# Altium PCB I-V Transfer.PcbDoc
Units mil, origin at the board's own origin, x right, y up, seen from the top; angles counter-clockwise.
Board outline 6000 x 4000 mil, 2 copper layers (Top Layer, Bottom Layer); 23 components, 15 nets, 71 pads, 1 vias.

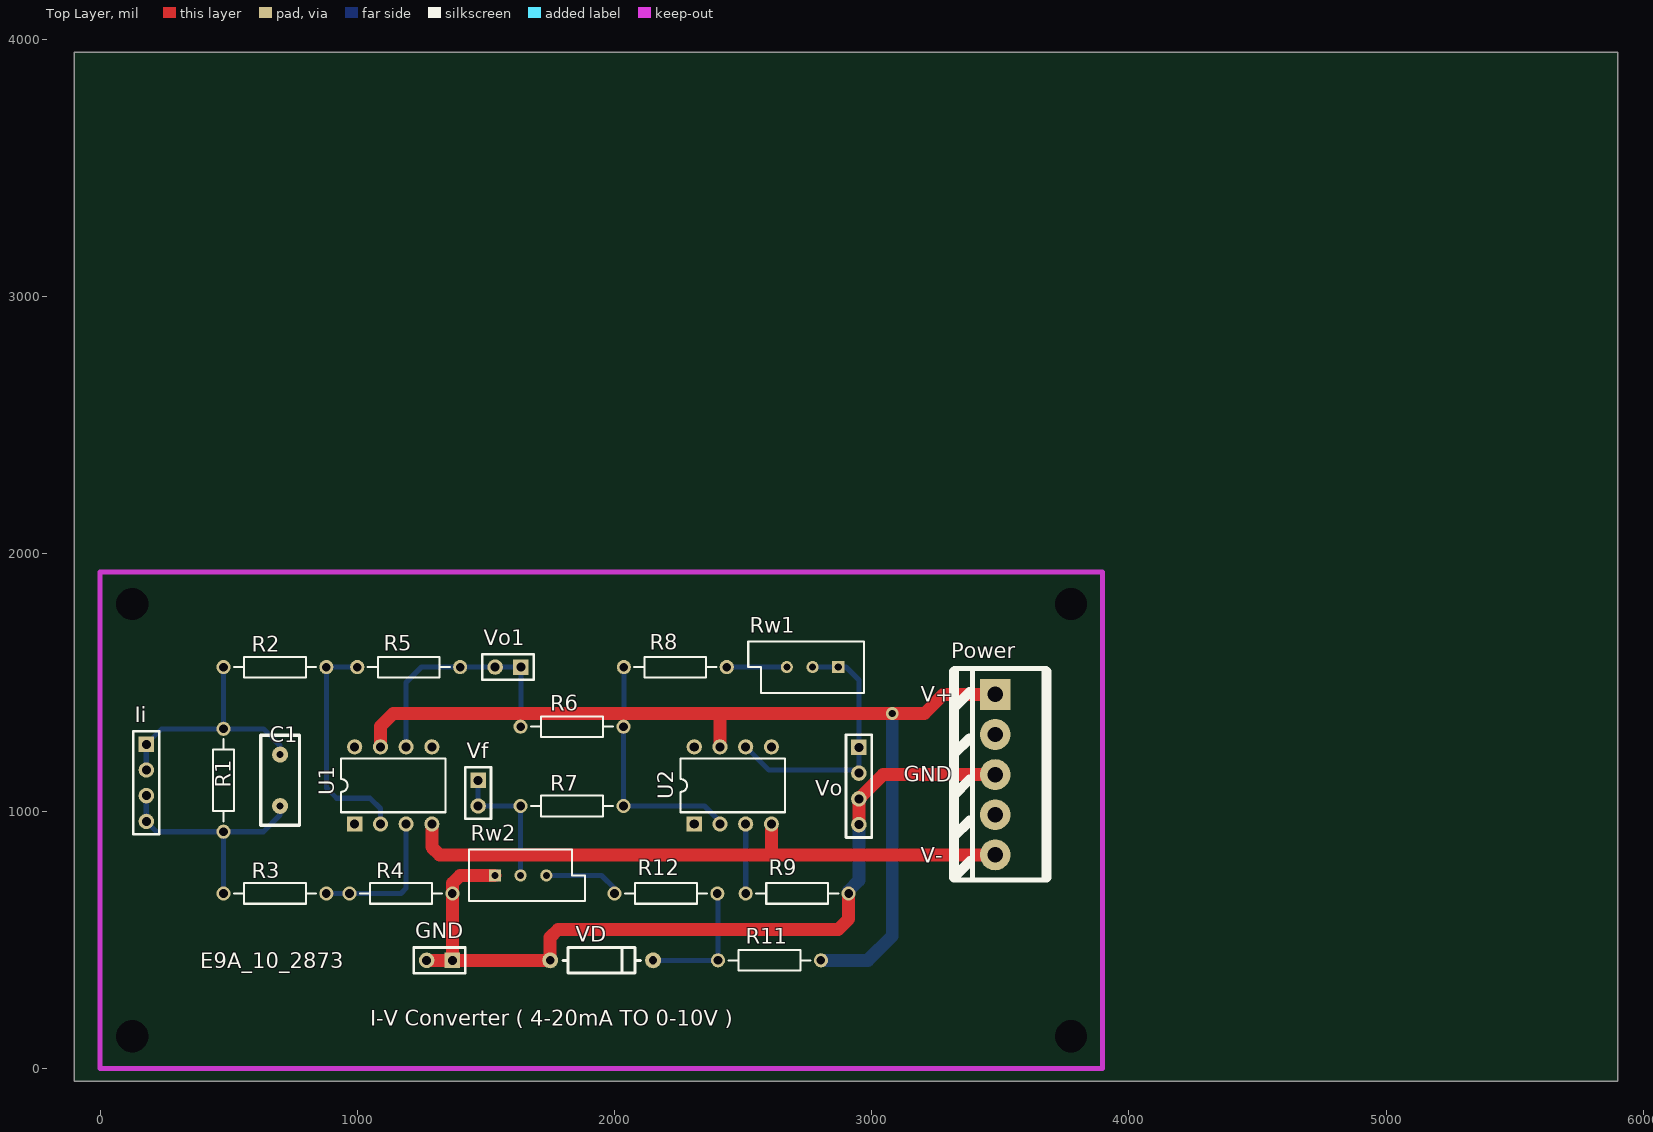
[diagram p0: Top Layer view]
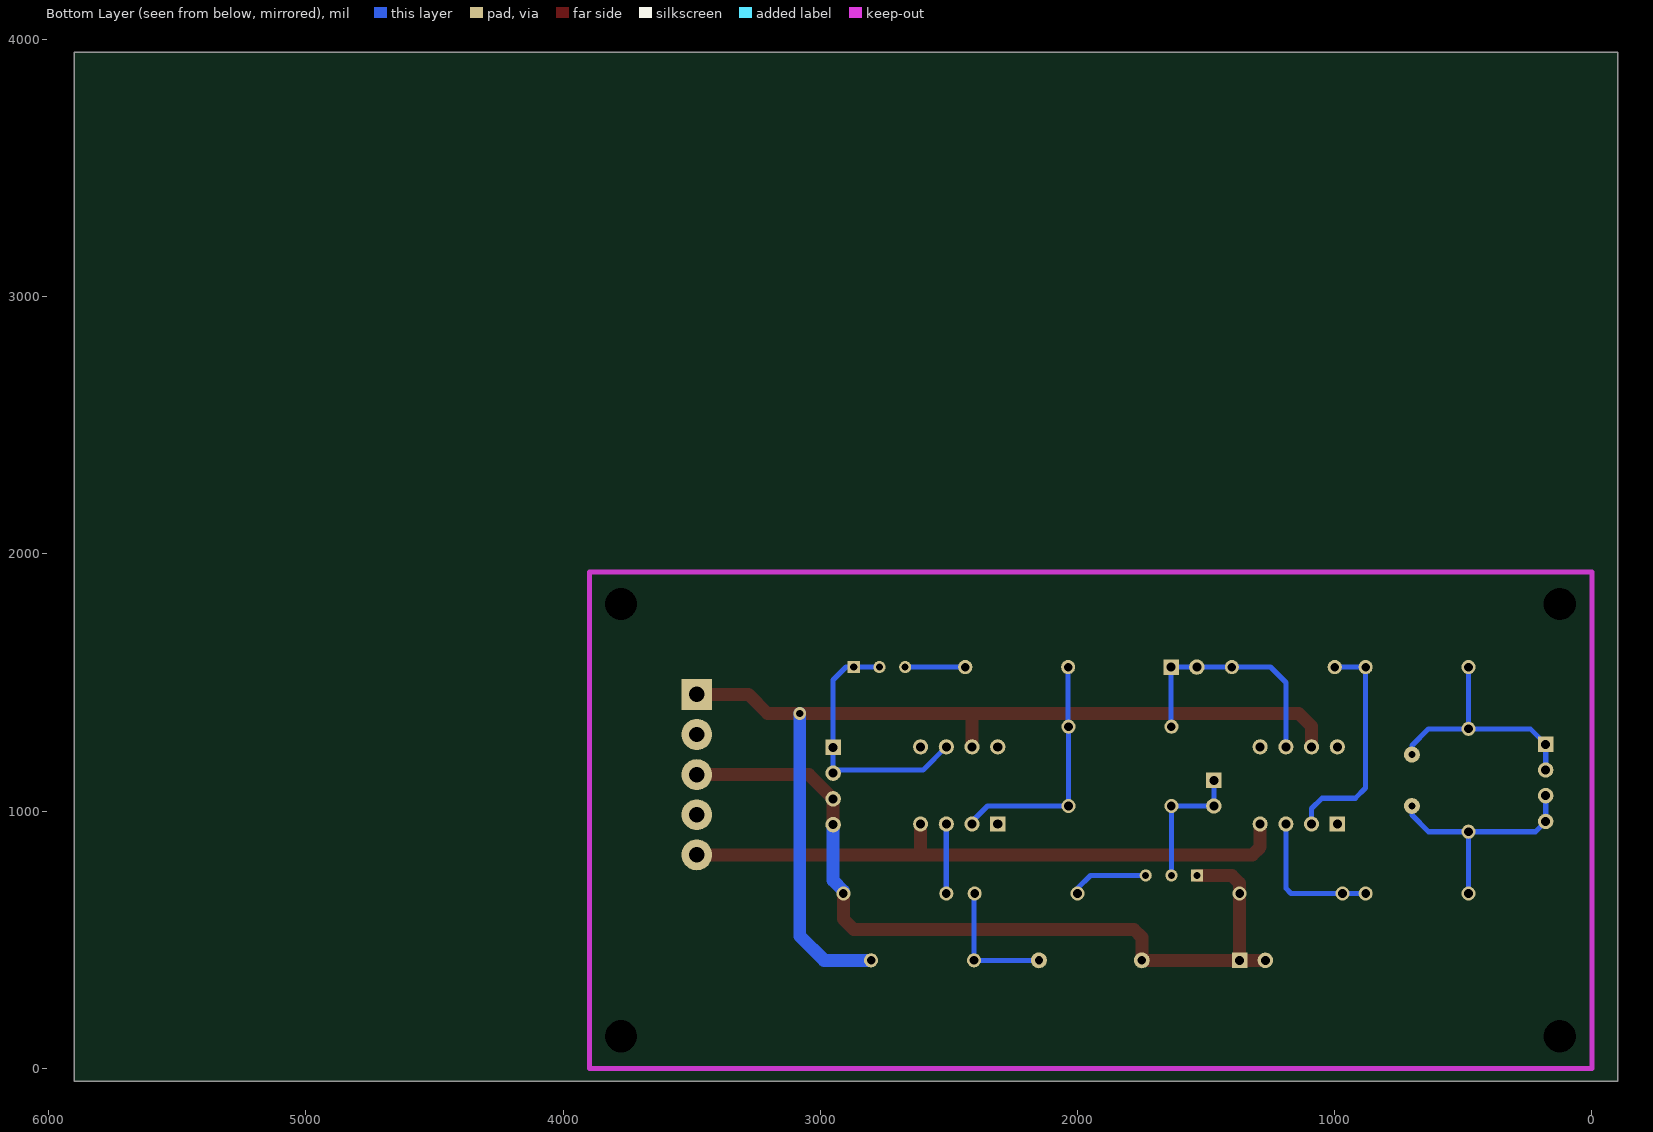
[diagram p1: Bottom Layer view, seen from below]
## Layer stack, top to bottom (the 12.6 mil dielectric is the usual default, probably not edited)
Top Layer: signal copper 1.4
Dielectric: dielectric 12.6, FR-4, Dk 4.8
Bottom Layer: signal copper 1.4

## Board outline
-100,-50 5900,-50 5900,3950 -100,3950

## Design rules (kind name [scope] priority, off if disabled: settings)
Clearance [All] p1 off: gap=10
DiffPairsRouting [All] p1 off: maxlimit=10 minlimit=10 mostfreqgap=10 maxuncoupledlength=500
FanoutControl Fanout_BGA [IsBGA] p1 off: bgadir=Out bgaviamode=Centered fanoutstyle=Auto fanoutdirection=Alternating viagrid=1 // Fanout_BGA (Default Rule)
FanoutControl Fanout_LCC [IsLCC] p2 off: bgadir=Out bgaviamode=Centered fanoutstyle=Auto fanoutdirection=Alternating viagrid=1 // Fanout_LCC (Default Rule)
FanoutControl Fanout_SOIC [IsSOIC] p3 off: bgadir=Out bgaviamode=Centered fanoutstyle=Auto fanoutdirection=Alternating viagrid=1 // Fanout_SOIC (Default Rule)
FanoutControl Fanout_Small [(CompPinCount < 5)] p4 off: bgadir=Out bgaviamode=Centered fanoutstyle=Auto fanoutdirection=OutThenIn viagrid=1 // Fanout_Small (Default Rule)
FanoutControl Fanout_Default [All] p5 off: bgadir=Out bgaviamode=Centered fanoutstyle=Auto fanoutdirection=Alternating viagrid=1 // Fanout_Default (Default Rule)
HoleSize [All] p1 off: absolutevalues=TRUE maxlimit=100 minlimit=1 maxpercent=80.000 minpercent=20.000
HoleToHoleClearance [All] p1 off: gap=10 allowstackedmicrovias=TRUE
LayerPairs [All] p1 off: enforce=TRUE
MinimumSolderMaskSliver [All] p1 off: minsoldermaskwidth=10
NetAntennae [All] p1 off: netantennaetolerance=0
PolygonConnect [All] p1: connectstyle=Relief reliefconductorwidth=10 reliefentries=4 polygonreliefangle="90 Angle"
RoomDefinition "I-V Transfer" [InComponentClass('I-V Transfer')] p1: confinementstyle=ConfineIn formatcopy=TRUE lockcomponents=FALSE outline -1100,-1050 900,-1050 900,-50 -1100,-50
RoutingCorners [All] p1 off: cornerstyle=45-Degree minsetback=100 maxsetback=100
RoutingLayers [All] p1 off: top layer_v5=TRUE bottom layer_v5=TRUE
RoutingPriority [All] p1 off: routingpriority=0
RoutingTopology [All] p1 off: topology=Shortest
RoutingVias [All] p1 off: holewidth=28 width=50 viastyle="Through Hole" minholewidth=28 minwidth=50 maxholewidth=28 maxwidth=50
ShortCircuit [All] p1 off: allowed=FALSE
SilkToSilkClearance [All] p1 off: silktosilkclearance=10
SilkscreenOverComponentPads [All] p1 off: minsilkscreentomaskgap=10
SolderMaskExpansion [All] p1: expansion=4
TestPointUsage [All] p1 off: valid=0 allowmultiple=FALSE
Testpoint [All] p1 off: side=15 testpointundercomponent=TRUE minsize=40 maxsize=100 preferedsize=60 minholesize=0 maxholesize=40 preferedholesize=32 testpointgrid=1 style=1023 order=0123456789
UnRoutedNet [All] p1 off:
Width [All] p1 off: maxlimit=50 minlimit=10 preferedwidth=10 toplayer_minwidth=50 toplayer_prefwidth=50 bottomlayer_minwidth=20 bottomlayer_maxwidth=20 bottomlayer_prefwidth=20 minimp=50.000000 maximp=50.000000 favimp=50.000000
5 further rules are at their usual default settings.

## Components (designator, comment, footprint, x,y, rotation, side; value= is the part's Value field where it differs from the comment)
C1 "Cap" RAD0.2 700,1020 r90 top
GND "Header 2" SIP-2 1370,420 r180 top
Ii "Header 4" SIP-4 180,1260 r270 top
Power "Header 5" "POWER PLUG5" 3480,1454 r90 top
R1 "Res2" AXIAL-0.4 480,1120 r90 top
R2 "Res2" AXIAL-0.4 680,1560 r0 top
R3 "Res2" AXIAL-0.4 680,680 r0 top
R4 "Res2" AXIAL-0.4 1170,680 r180 top
R5 "Res2" AXIAL-0.4 1200,1560 r0 top
R6 "Res2" AXIAL-0.4 1834.88,1328.35 r0 top
R7 "Res2" AXIAL-0.4 1834.88,1020 r0 top
R8 "Res2" AXIAL-0.4 2236.46,1560 r0 top
R9 "Res2" AXIAL-0.4 2710,680 r180 top
R11 "Res2" AXIAL-0.4 2602.6,420 r180 top
R12 "Res2" AXIAL-0.4 2200,680 r180 top
Rw1 "RPot" VR5 2770,1560 r180 top
Rw2 "RPot" VR5 1635,750 r0 top
U1 "OP-07" DIP-8 1140,1100 r0 top
U2 "OP-07" DIP-8 2460,1100 r0 top
VD "5.1V" DIODE0.4 1750,420 r0 top
Vf "Header 2" SIP-2 1470,1120 r270 top
Vo "Header 4" SIP-4 2950,1247.64 r270 top
Vo1 "Header 2" SIP-2 1636.06,1560 r180 top

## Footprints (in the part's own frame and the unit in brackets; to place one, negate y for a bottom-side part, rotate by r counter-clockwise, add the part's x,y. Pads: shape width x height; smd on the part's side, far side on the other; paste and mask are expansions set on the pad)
AXIAL-0.4 [mm] "Resistor; 2 Leads"
  round 1.4 hole 0.85: 1(-5.08,0) 2(5.08,0)
  silkscreen extent -4.06,-1.02 4.06,1.02
DIODE0.4 [mil]
  round 62 hole 32: 1(0,0) 2(400,0)
  silkscreen extent 50,-50 350,50
DIP-8 [mm] "DIP; 8 Leads; Row Spacing 7.62 mm; Pitch 2.54 mm"
  rect 1.5x1.5 hole 0.9: 1(-3.81,-3.81)
  round 1.5 hole 0.9: 2(-1.27,-3.81) 3(1.27,-3.81) 4(3.81,-3.81) 5(3.81,3.81) 6(1.27,3.81) 7(-1.27,3.81) 8(-3.81,3.81)
  silkscreen extent -5.15,-2.65 5.15,2.65
"POWER PLUG5" [mil] "双电源插座"
  rect 120x120 hole 60: 1(0,0)
  round 120 hole 60: 2(-156,0) 3(-312,0) 4(-468,0) 5(-624,0)
  silkscreen extent -722,-200 100,160
RAD0.2 [mil]
  round 62 hole 28: 1(0,0) 2(200,0)
  silkscreen extent -75,-75 275,75
SIP-2 [mil]
  rect 60x60 hole 35: 1(0,0)
  round 60 hole 35: 2(100,0)
  silkscreen extent -50,-50 150,50
SIP-4 [mil]
  rect 60x60 hole 35: 1(0,0)
  round 60 hole 35: 2(100,0) 3(200,0) 4(300,0)
  silkscreen extent -50,-50 350,50
VR5 [mm] "Potentiometer; 3 Leads"
  rect 1.2x1.2 hole 0.7: 1(-2.54,0)
  round 1.2 hole 0.7: 2(0,0) 3(2.54,0)
  silkscreen extent -5.08,-2.54 6.35,2.54

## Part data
C1: "Capacitor"
GND Vf Vo1: "Header, 2-Pin"
Ii Vo: "Header, 4-Pin"
Power: "Header, 5-Pin"
R1 R2 R3 R4 R5 R6 R7 R8 R9 R11 R12: "Resistor"
Rw1 Rw2: "Potentiometer"
VD: library part "Diode 11DQ03", "Schottky Rectifier"

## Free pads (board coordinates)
  round 60 hole 125: 3(125,125) 3(125,1805) 3(3775,125) 3(3775,1805)

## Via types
v1: diameter 50, hole 28, Top Layer to Bottom Layer, 1 vias

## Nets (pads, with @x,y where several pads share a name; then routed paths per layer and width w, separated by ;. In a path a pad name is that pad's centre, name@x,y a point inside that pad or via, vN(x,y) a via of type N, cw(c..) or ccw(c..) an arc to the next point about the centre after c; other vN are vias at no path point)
+12V: Power.1 R11.1 U1.7 U2.7 | length 3833.1
  Top Layer w50: U1.7 1090,1330 1140,1380 2410,1380 ; U2.7 2410,1380 ; Power.1 3279,1454 3205,1380 2410,1380
  Bottom Layer w50: R11.1 2985,420 3080,515 v1(3080,1380)
-12V: Power.5 U1.4 U2.4 | length 2412.4
  Top Layer w50: U1.4 1290,860 1320,830 2610,830 ; U2.4 2610,830 ; Power.5 2610,830
GND: GND.1 GND.2 Power.3 R4.1 R9.1 Rw2.1 VD.1 Vo.3 Vo.4 | length 3289.7
  Top Layer w50: GND.2 GND.1 ; Rw2.1 1400,750 1370,720 R4.1 GND.1 ; R9.1 2910,580 2870,540 1780,540 1750,510 VD.1 GND.1 ; Vo.4 Vo.3 3044.36,1142 Power.3
  Bottom Layer w20: R9.1 R9.1@2910,690
  Bottom Layer w50: R9.1@2910,690 2950,730 Vo.4
NetC1_1: C1.1 Ii.3 Ii.4 R1.1 R3.1 | length 938.5
  Bottom Layer w20: Ii.3 Ii.4 220,920 R1.1 ; R3.1 R1.1 ; C1.1 700,985 635,920 R1.1
NetC1_2: C1.2 Ii.1 Ii.2 R1.2 R2.1 | length 946.8
  Bottom Layer w20: Ii.2 Ii.1 240,1320 R1.2 ; R2.1 R1.2 ; C1.2 700,1255 635,1320 R1.2
NetR2_2: R2.2 R5.1 U1.2 | length 893.1
  Bottom Layer w20: R5.1 R2.2 880,1090 920,1050 1050,1050 1090,1010 U1.2
NetR3_2: R3.2 R4.2 U1.3 | length 568.3
  Bottom Layer w20: R3.2 R4.2 1170,680 1190,700 U1.3
NetR5_2: R5.2 R6.1 U1.6 Vo1.1 Vo1.2 | length 954.7
  Bottom Layer w20: U1.6 1190,1500 1250,1560 R5.2 Vo1.2 Vo1.1 R6.1@1636.06,1329.53 ; R6.1@1636.06,1329.53 R6.1 R6.1@1636.06,1329.53
NetR6_2: R6.2 R7.2 R8.1 U2.2 | length 950.6
  Bottom Layer w20: R8.1 2036.46,1329.92 R6.2 R7.2 2350,1020 2410,960 U2.2
NetR7_1: R7.1 Rw2.2 Vf.1 Vf.2 | length 534.9
  Bottom Layer w20: Vf.1 Vf.2 R7.1 1634.88,750.12 Rw2.2
NetR8_2: R8.2 Rw1.3 | length 233.5
  Bottom Layer w20: R8.2 Rw1.3
NetR9_2: R9.2 U2.3 | length 270
  Bottom Layer w20: R9.2 U2.3
NetR11_2: R11.2 R12.1 VD.2 | length 513.7
  Bottom Layer w20: VD.2 R11.2 2402.6,677.4 R12.1
NetR12_2: R12.2 Rw2.3 | length 305.7
  Bottom Layer w20: Rw2.3 1950,750 2000,700 R12.2
NetRw1_1: Rw1.1 Rw1.2 U2.6 Vo.1 Vo.2 | length 1045.5
  Bottom Layer w20: U2.6 2600,1160 2937.64,1160 Vo.2 Vo.1 2950,1510 2900,1560 Rw1.1 Rw1.2
pads on no net: Power.2 Power.4 U1.1 U1.5 U1.8 U2.1 U2.5 U2.8

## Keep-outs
Keep-Out Layer:
  lines w20: 0,1929.13 0,0 3897.64,0 3897.64,1929.13 0,1929.13 ; 0,1929.13 0,1929.13

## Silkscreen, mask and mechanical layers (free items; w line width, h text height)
Top Overlay:
  text "V+" at 3190,1425 h60
  text "GND" at 3125,1115 h60
  text "V-" at 3190,800 h60
  text "E9A_10_2873" at 390,390 h60
  text "I-V Converter ( 4-20mA TO 0-10V )" at 1050,165 h60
